VERSION 5.7 ;
BUSBITCHARS "[]" ;
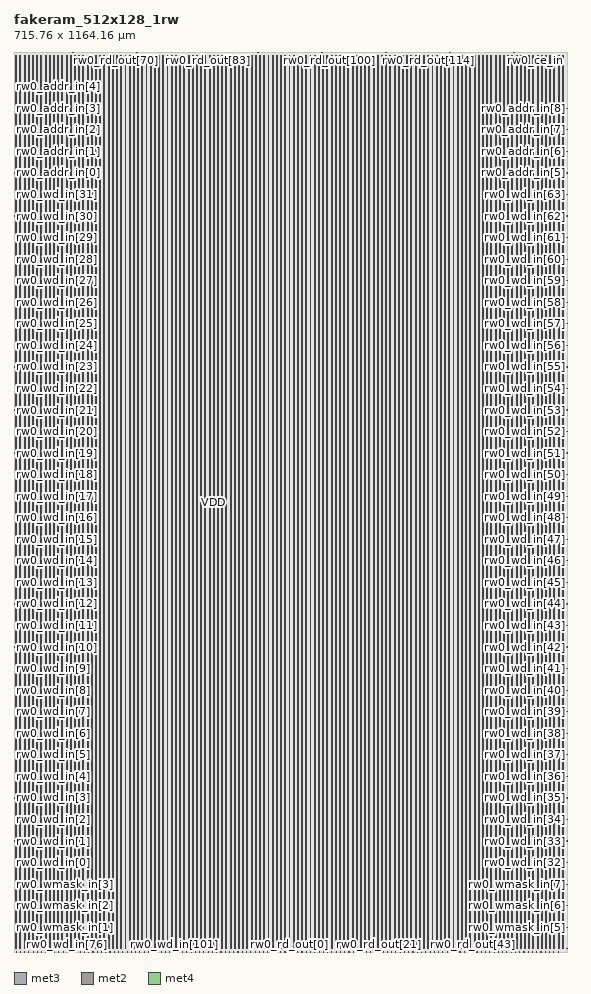
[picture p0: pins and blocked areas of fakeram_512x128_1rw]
MACRO fakeram_512x128_1rw
  FOREIGN fakeram_512x128_1rw 0 0 ;
  SYMMETRY X Y R90 ;
  SIZE 715.760 BY 1164.160 ;
  CLASS BLOCK ;
  PIN rw0_wmask_in[0]
    DIRECTION INPUT ;
    USE SIGNAL ;
    SHAPE ABUTMENT ;
    PORT
      LAYER met3 ;
      RECT 0.000 3.930 0.900 4.230 ;
    END
  END rw0_wmask_in[0]
  PIN rw0_wmask_in[1]
    DIRECTION INPUT ;
    USE SIGNAL ;
    SHAPE ABUTMENT ;
    PORT
      LAYER met3 ;
      RECT 0.000 31.810 0.900 32.110 ;
    END
  END rw0_wmask_in[1]
  PIN rw0_wmask_in[2]
    DIRECTION INPUT ;
    USE SIGNAL ;
    SHAPE ABUTMENT ;
    PORT
      LAYER met3 ;
      RECT 0.000 59.690 0.900 59.990 ;
    END
  END rw0_wmask_in[2]
  PIN rw0_wmask_in[3]
    DIRECTION INPUT ;
    USE SIGNAL ;
    SHAPE ABUTMENT ;
    PORT
      LAYER met3 ;
      RECT 0.000 87.570 0.900 87.870 ;
    END
  END rw0_wmask_in[3]
  PIN rw0_wmask_in[4]
    DIRECTION INPUT ;
    USE SIGNAL ;
    SHAPE ABUTMENT ;
    PORT
      LAYER met3 ;
      RECT 714.860 3.930 715.760 4.230 ;
    END
  END rw0_wmask_in[4]
  PIN rw0_wmask_in[5]
    DIRECTION INPUT ;
    USE SIGNAL ;
    SHAPE ABUTMENT ;
    PORT
      LAYER met3 ;
      RECT 714.860 31.810 715.760 32.110 ;
    END
  END rw0_wmask_in[5]
  PIN rw0_wmask_in[6]
    DIRECTION INPUT ;
    USE SIGNAL ;
    SHAPE ABUTMENT ;
    PORT
      LAYER met3 ;
      RECT 714.860 59.690 715.760 59.990 ;
    END
  END rw0_wmask_in[6]
  PIN rw0_wmask_in[7]
    DIRECTION INPUT ;
    USE SIGNAL ;
    SHAPE ABUTMENT ;
    PORT
      LAYER met3 ;
      RECT 714.860 87.570 715.760 87.870 ;
    END
  END rw0_wmask_in[7]
  PIN rw0_wmask_in[8]
    DIRECTION INPUT ;
    USE SIGNAL ;
    SHAPE ABUTMENT ;
    PORT
      LAYER met2 ;
      RECT 2.690 1163.740 2.830 1164.160 ;
    END
  END rw0_wmask_in[8]
  PIN rw0_wmask_in[9]
    DIRECTION INPUT ;
    USE SIGNAL ;
    SHAPE ABUTMENT ;
    PORT
      LAYER met2 ;
      RECT 11.890 1163.740 12.030 1164.160 ;
    END
  END rw0_wmask_in[9]
  PIN rw0_wmask_in[10]
    DIRECTION INPUT ;
    USE SIGNAL ;
    SHAPE ABUTMENT ;
    PORT
      LAYER met2 ;
      RECT 21.090 1163.740 21.230 1164.160 ;
    END
  END rw0_wmask_in[10]
  PIN rw0_wmask_in[11]
    DIRECTION INPUT ;
    USE SIGNAL ;
    SHAPE ABUTMENT ;
    PORT
      LAYER met2 ;
      RECT 30.290 1163.740 30.430 1164.160 ;
    END
  END rw0_wmask_in[11]
  PIN rw0_wmask_in[12]
    DIRECTION INPUT ;
    USE SIGNAL ;
    SHAPE ABUTMENT ;
    PORT
      LAYER met2 ;
      RECT 39.490 1163.740 39.630 1164.160 ;
    END
  END rw0_wmask_in[12]
  PIN rw0_wmask_in[13]
    DIRECTION INPUT ;
    USE SIGNAL ;
    SHAPE ABUTMENT ;
    PORT
      LAYER met2 ;
      RECT 48.690 1163.740 48.830 1164.160 ;
    END
  END rw0_wmask_in[13]
  PIN rw0_wmask_in[14]
    DIRECTION INPUT ;
    USE SIGNAL ;
    SHAPE ABUTMENT ;
    PORT
      LAYER met2 ;
      RECT 57.890 1163.740 58.030 1164.160 ;
    END
  END rw0_wmask_in[14]
  PIN rw0_wmask_in[15]
    DIRECTION INPUT ;
    USE SIGNAL ;
    SHAPE ABUTMENT ;
    PORT
      LAYER met2 ;
      RECT 67.090 1163.740 67.230 1164.160 ;
    END
  END rw0_wmask_in[15]
  PIN rw0_wd_in[0]
    DIRECTION INPUT ;
    USE SIGNAL ;
    SHAPE ABUTMENT ;
    PORT
      LAYER met3 ;
      RECT 0.000 115.450 0.900 115.750 ;
    END
  END rw0_wd_in[0]
  PIN rw0_wd_in[1]
    DIRECTION INPUT ;
    USE SIGNAL ;
    SHAPE ABUTMENT ;
    PORT
      LAYER met3 ;
      RECT 0.000 143.330 0.900 143.630 ;
    END
  END rw0_wd_in[1]
  PIN rw0_wd_in[2]
    DIRECTION INPUT ;
    USE SIGNAL ;
    SHAPE ABUTMENT ;
    PORT
      LAYER met3 ;
      RECT 0.000 171.210 0.900 171.510 ;
    END
  END rw0_wd_in[2]
  PIN rw0_wd_in[3]
    DIRECTION INPUT ;
    USE SIGNAL ;
    SHAPE ABUTMENT ;
    PORT
      LAYER met3 ;
      RECT 0.000 199.090 0.900 199.390 ;
    END
  END rw0_wd_in[3]
  PIN rw0_wd_in[4]
    DIRECTION INPUT ;
    USE SIGNAL ;
    SHAPE ABUTMENT ;
    PORT
      LAYER met3 ;
      RECT 0.000 226.970 0.900 227.270 ;
    END
  END rw0_wd_in[4]
  PIN rw0_wd_in[5]
    DIRECTION INPUT ;
    USE SIGNAL ;
    SHAPE ABUTMENT ;
    PORT
      LAYER met3 ;
      RECT 0.000 254.850 0.900 255.150 ;
    END
  END rw0_wd_in[5]
  PIN rw0_wd_in[6]
    DIRECTION INPUT ;
    USE SIGNAL ;
    SHAPE ABUTMENT ;
    PORT
      LAYER met3 ;
      RECT 0.000 282.730 0.900 283.030 ;
    END
  END rw0_wd_in[6]
  PIN rw0_wd_in[7]
    DIRECTION INPUT ;
    USE SIGNAL ;
    SHAPE ABUTMENT ;
    PORT
      LAYER met3 ;
      RECT 0.000 310.610 0.900 310.910 ;
    END
  END rw0_wd_in[7]
  PIN rw0_wd_in[8]
    DIRECTION INPUT ;
    USE SIGNAL ;
    SHAPE ABUTMENT ;
    PORT
      LAYER met3 ;
      RECT 0.000 338.490 0.900 338.790 ;
    END
  END rw0_wd_in[8]
  PIN rw0_wd_in[9]
    DIRECTION INPUT ;
    USE SIGNAL ;
    SHAPE ABUTMENT ;
    PORT
      LAYER met3 ;
      RECT 0.000 366.370 0.900 366.670 ;
    END
  END rw0_wd_in[9]
  PIN rw0_wd_in[10]
    DIRECTION INPUT ;
    USE SIGNAL ;
    SHAPE ABUTMENT ;
    PORT
      LAYER met3 ;
      RECT 0.000 394.250 0.900 394.550 ;
    END
  END rw0_wd_in[10]
  PIN rw0_wd_in[11]
    DIRECTION INPUT ;
    USE SIGNAL ;
    SHAPE ABUTMENT ;
    PORT
      LAYER met3 ;
      RECT 0.000 422.130 0.900 422.430 ;
    END
  END rw0_wd_in[11]
  PIN rw0_wd_in[12]
    DIRECTION INPUT ;
    USE SIGNAL ;
    SHAPE ABUTMENT ;
    PORT
      LAYER met3 ;
      RECT 0.000 450.010 0.900 450.310 ;
    END
  END rw0_wd_in[12]
  PIN rw0_wd_in[13]
    DIRECTION INPUT ;
    USE SIGNAL ;
    SHAPE ABUTMENT ;
    PORT
      LAYER met3 ;
      RECT 0.000 477.890 0.900 478.190 ;
    END
  END rw0_wd_in[13]
  PIN rw0_wd_in[14]
    DIRECTION INPUT ;
    USE SIGNAL ;
    SHAPE ABUTMENT ;
    PORT
      LAYER met3 ;
      RECT 0.000 505.770 0.900 506.070 ;
    END
  END rw0_wd_in[14]
  PIN rw0_wd_in[15]
    DIRECTION INPUT ;
    USE SIGNAL ;
    SHAPE ABUTMENT ;
    PORT
      LAYER met3 ;
      RECT 0.000 533.650 0.900 533.950 ;
    END
  END rw0_wd_in[15]
  PIN rw0_wd_in[16]
    DIRECTION INPUT ;
    USE SIGNAL ;
    SHAPE ABUTMENT ;
    PORT
      LAYER met3 ;
      RECT 0.000 561.530 0.900 561.830 ;
    END
  END rw0_wd_in[16]
  PIN rw0_wd_in[17]
    DIRECTION INPUT ;
    USE SIGNAL ;
    SHAPE ABUTMENT ;
    PORT
      LAYER met3 ;
      RECT 0.000 589.410 0.900 589.710 ;
    END
  END rw0_wd_in[17]
  PIN rw0_wd_in[18]
    DIRECTION INPUT ;
    USE SIGNAL ;
    SHAPE ABUTMENT ;
    PORT
      LAYER met3 ;
      RECT 0.000 617.290 0.900 617.590 ;
    END
  END rw0_wd_in[18]
  PIN rw0_wd_in[19]
    DIRECTION INPUT ;
    USE SIGNAL ;
    SHAPE ABUTMENT ;
    PORT
      LAYER met3 ;
      RECT 0.000 645.170 0.900 645.470 ;
    END
  END rw0_wd_in[19]
  PIN rw0_wd_in[20]
    DIRECTION INPUT ;
    USE SIGNAL ;
    SHAPE ABUTMENT ;
    PORT
      LAYER met3 ;
      RECT 0.000 673.050 0.900 673.350 ;
    END
  END rw0_wd_in[20]
  PIN rw0_wd_in[21]
    DIRECTION INPUT ;
    USE SIGNAL ;
    SHAPE ABUTMENT ;
    PORT
      LAYER met3 ;
      RECT 0.000 700.930 0.900 701.230 ;
    END
  END rw0_wd_in[21]
  PIN rw0_wd_in[22]
    DIRECTION INPUT ;
    USE SIGNAL ;
    SHAPE ABUTMENT ;
    PORT
      LAYER met3 ;
      RECT 0.000 728.810 0.900 729.110 ;
    END
  END rw0_wd_in[22]
  PIN rw0_wd_in[23]
    DIRECTION INPUT ;
    USE SIGNAL ;
    SHAPE ABUTMENT ;
    PORT
      LAYER met3 ;
      RECT 0.000 756.690 0.900 756.990 ;
    END
  END rw0_wd_in[23]
  PIN rw0_wd_in[24]
    DIRECTION INPUT ;
    USE SIGNAL ;
    SHAPE ABUTMENT ;
    PORT
      LAYER met3 ;
      RECT 0.000 784.570 0.900 784.870 ;
    END
  END rw0_wd_in[24]
  PIN rw0_wd_in[25]
    DIRECTION INPUT ;
    USE SIGNAL ;
    SHAPE ABUTMENT ;
    PORT
      LAYER met3 ;
      RECT 0.000 812.450 0.900 812.750 ;
    END
  END rw0_wd_in[25]
  PIN rw0_wd_in[26]
    DIRECTION INPUT ;
    USE SIGNAL ;
    SHAPE ABUTMENT ;
    PORT
      LAYER met3 ;
      RECT 0.000 840.330 0.900 840.630 ;
    END
  END rw0_wd_in[26]
  PIN rw0_wd_in[27]
    DIRECTION INPUT ;
    USE SIGNAL ;
    SHAPE ABUTMENT ;
    PORT
      LAYER met3 ;
      RECT 0.000 868.210 0.900 868.510 ;
    END
  END rw0_wd_in[27]
  PIN rw0_wd_in[28]
    DIRECTION INPUT ;
    USE SIGNAL ;
    SHAPE ABUTMENT ;
    PORT
      LAYER met3 ;
      RECT 0.000 896.090 0.900 896.390 ;
    END
  END rw0_wd_in[28]
  PIN rw0_wd_in[29]
    DIRECTION INPUT ;
    USE SIGNAL ;
    SHAPE ABUTMENT ;
    PORT
      LAYER met3 ;
      RECT 0.000 923.970 0.900 924.270 ;
    END
  END rw0_wd_in[29]
  PIN rw0_wd_in[30]
    DIRECTION INPUT ;
    USE SIGNAL ;
    SHAPE ABUTMENT ;
    PORT
      LAYER met3 ;
      RECT 0.000 951.850 0.900 952.150 ;
    END
  END rw0_wd_in[30]
  PIN rw0_wd_in[31]
    DIRECTION INPUT ;
    USE SIGNAL ;
    SHAPE ABUTMENT ;
    PORT
      LAYER met3 ;
      RECT 0.000 979.730 0.900 980.030 ;
    END
  END rw0_wd_in[31]
  PIN rw0_wd_in[32]
    DIRECTION INPUT ;
    USE SIGNAL ;
    SHAPE ABUTMENT ;
    PORT
      LAYER met3 ;
      RECT 714.860 115.450 715.760 115.750 ;
    END
  END rw0_wd_in[32]
  PIN rw0_wd_in[33]
    DIRECTION INPUT ;
    USE SIGNAL ;
    SHAPE ABUTMENT ;
    PORT
      LAYER met3 ;
      RECT 714.860 143.330 715.760 143.630 ;
    END
  END rw0_wd_in[33]
  PIN rw0_wd_in[34]
    DIRECTION INPUT ;
    USE SIGNAL ;
    SHAPE ABUTMENT ;
    PORT
      LAYER met3 ;
      RECT 714.860 171.210 715.760 171.510 ;
    END
  END rw0_wd_in[34]
  PIN rw0_wd_in[35]
    DIRECTION INPUT ;
    USE SIGNAL ;
    SHAPE ABUTMENT ;
    PORT
      LAYER met3 ;
      RECT 714.860 199.090 715.760 199.390 ;
    END
  END rw0_wd_in[35]
  PIN rw0_wd_in[36]
    DIRECTION INPUT ;
    USE SIGNAL ;
    SHAPE ABUTMENT ;
    PORT
      LAYER met3 ;
      RECT 714.860 226.970 715.760 227.270 ;
    END
  END rw0_wd_in[36]
  PIN rw0_wd_in[37]
    DIRECTION INPUT ;
    USE SIGNAL ;
    SHAPE ABUTMENT ;
    PORT
      LAYER met3 ;
      RECT 714.860 254.850 715.760 255.150 ;
    END
  END rw0_wd_in[37]
  PIN rw0_wd_in[38]
    DIRECTION INPUT ;
    USE SIGNAL ;
    SHAPE ABUTMENT ;
    PORT
      LAYER met3 ;
      RECT 714.860 282.730 715.760 283.030 ;
    END
  END rw0_wd_in[38]
  PIN rw0_wd_in[39]
    DIRECTION INPUT ;
    USE SIGNAL ;
    SHAPE ABUTMENT ;
    PORT
      LAYER met3 ;
      RECT 714.860 310.610 715.760 310.910 ;
    END
  END rw0_wd_in[39]
  PIN rw0_wd_in[40]
    DIRECTION INPUT ;
    USE SIGNAL ;
    SHAPE ABUTMENT ;
    PORT
      LAYER met3 ;
      RECT 714.860 338.490 715.760 338.790 ;
    END
  END rw0_wd_in[40]
  PIN rw0_wd_in[41]
    DIRECTION INPUT ;
    USE SIGNAL ;
    SHAPE ABUTMENT ;
    PORT
      LAYER met3 ;
      RECT 714.860 366.370 715.760 366.670 ;
    END
  END rw0_wd_in[41]
  PIN rw0_wd_in[42]
    DIRECTION INPUT ;
    USE SIGNAL ;
    SHAPE ABUTMENT ;
    PORT
      LAYER met3 ;
      RECT 714.860 394.250 715.760 394.550 ;
    END
  END rw0_wd_in[42]
  PIN rw0_wd_in[43]
    DIRECTION INPUT ;
    USE SIGNAL ;
    SHAPE ABUTMENT ;
    PORT
      LAYER met3 ;
      RECT 714.860 422.130 715.760 422.430 ;
    END
  END rw0_wd_in[43]
  PIN rw0_wd_in[44]
    DIRECTION INPUT ;
    USE SIGNAL ;
    SHAPE ABUTMENT ;
    PORT
      LAYER met3 ;
      RECT 714.860 450.010 715.760 450.310 ;
    END
  END rw0_wd_in[44]
  PIN rw0_wd_in[45]
    DIRECTION INPUT ;
    USE SIGNAL ;
    SHAPE ABUTMENT ;
    PORT
      LAYER met3 ;
      RECT 714.860 477.890 715.760 478.190 ;
    END
  END rw0_wd_in[45]
  PIN rw0_wd_in[46]
    DIRECTION INPUT ;
    USE SIGNAL ;
    SHAPE ABUTMENT ;
    PORT
      LAYER met3 ;
      RECT 714.860 505.770 715.760 506.070 ;
    END
  END rw0_wd_in[46]
  PIN rw0_wd_in[47]
    DIRECTION INPUT ;
    USE SIGNAL ;
    SHAPE ABUTMENT ;
    PORT
      LAYER met3 ;
      RECT 714.860 533.650 715.760 533.950 ;
    END
  END rw0_wd_in[47]
  PIN rw0_wd_in[48]
    DIRECTION INPUT ;
    USE SIGNAL ;
    SHAPE ABUTMENT ;
    PORT
      LAYER met3 ;
      RECT 714.860 561.530 715.760 561.830 ;
    END
  END rw0_wd_in[48]
  PIN rw0_wd_in[49]
    DIRECTION INPUT ;
    USE SIGNAL ;
    SHAPE ABUTMENT ;
    PORT
      LAYER met3 ;
      RECT 714.860 589.410 715.760 589.710 ;
    END
  END rw0_wd_in[49]
  PIN rw0_wd_in[50]
    DIRECTION INPUT ;
    USE SIGNAL ;
    SHAPE ABUTMENT ;
    PORT
      LAYER met3 ;
      RECT 714.860 617.290 715.760 617.590 ;
    END
  END rw0_wd_in[50]
  PIN rw0_wd_in[51]
    DIRECTION INPUT ;
    USE SIGNAL ;
    SHAPE ABUTMENT ;
    PORT
      LAYER met3 ;
      RECT 714.860 645.170 715.760 645.470 ;
    END
  END rw0_wd_in[51]
  PIN rw0_wd_in[52]
    DIRECTION INPUT ;
    USE SIGNAL ;
    SHAPE ABUTMENT ;
    PORT
      LAYER met3 ;
      RECT 714.860 673.050 715.760 673.350 ;
    END
  END rw0_wd_in[52]
  PIN rw0_wd_in[53]
    DIRECTION INPUT ;
    USE SIGNAL ;
    SHAPE ABUTMENT ;
    PORT
      LAYER met3 ;
      RECT 714.860 700.930 715.760 701.230 ;
    END
  END rw0_wd_in[53]
  PIN rw0_wd_in[54]
    DIRECTION INPUT ;
    USE SIGNAL ;
    SHAPE ABUTMENT ;
    PORT
      LAYER met3 ;
      RECT 714.860 728.810 715.760 729.110 ;
    END
  END rw0_wd_in[54]
  PIN rw0_wd_in[55]
    DIRECTION INPUT ;
    USE SIGNAL ;
    SHAPE ABUTMENT ;
    PORT
      LAYER met3 ;
      RECT 714.860 756.690 715.760 756.990 ;
    END
  END rw0_wd_in[55]
  PIN rw0_wd_in[56]
    DIRECTION INPUT ;
    USE SIGNAL ;
    SHAPE ABUTMENT ;
    PORT
      LAYER met3 ;
      RECT 714.860 784.570 715.760 784.870 ;
    END
  END rw0_wd_in[56]
  PIN rw0_wd_in[57]
    DIRECTION INPUT ;
    USE SIGNAL ;
    SHAPE ABUTMENT ;
    PORT
      LAYER met3 ;
      RECT 714.860 812.450 715.760 812.750 ;
    END
  END rw0_wd_in[57]
  PIN rw0_wd_in[58]
    DIRECTION INPUT ;
    USE SIGNAL ;
    SHAPE ABUTMENT ;
    PORT
      LAYER met3 ;
      RECT 714.860 840.330 715.760 840.630 ;
    END
  END rw0_wd_in[58]
  PIN rw0_wd_in[59]
    DIRECTION INPUT ;
    USE SIGNAL ;
    SHAPE ABUTMENT ;
    PORT
      LAYER met3 ;
      RECT 714.860 868.210 715.760 868.510 ;
    END
  END rw0_wd_in[59]
  PIN rw0_wd_in[60]
    DIRECTION INPUT ;
    USE SIGNAL ;
    SHAPE ABUTMENT ;
    PORT
      LAYER met3 ;
      RECT 714.860 896.090 715.760 896.390 ;
    END
  END rw0_wd_in[60]
  PIN rw0_wd_in[61]
    DIRECTION INPUT ;
    USE SIGNAL ;
    SHAPE ABUTMENT ;
    PORT
      LAYER met3 ;
      RECT 714.860 923.970 715.760 924.270 ;
    END
  END rw0_wd_in[61]
  PIN rw0_wd_in[62]
    DIRECTION INPUT ;
    USE SIGNAL ;
    SHAPE ABUTMENT ;
    PORT
      LAYER met3 ;
      RECT 714.860 951.850 715.760 952.150 ;
    END
  END rw0_wd_in[62]
  PIN rw0_wd_in[63]
    DIRECTION INPUT ;
    USE SIGNAL ;
    SHAPE ABUTMENT ;
    PORT
      LAYER met3 ;
      RECT 714.860 979.730 715.760 980.030 ;
    END
  END rw0_wd_in[63]
  PIN rw0_wd_in[64]
    DIRECTION INPUT ;
    USE SIGNAL ;
    SHAPE ABUTMENT ;
    PORT
      LAYER met2 ;
      RECT 2.690 0.000 2.830 0.420 ;
    END
  END rw0_wd_in[64]
  PIN rw0_wd_in[65]
    DIRECTION INPUT ;
    USE SIGNAL ;
    SHAPE ABUTMENT ;
    PORT
      LAYER met2 ;
      RECT 8.210 0.000 8.350 0.420 ;
    END
  END rw0_wd_in[65]
  PIN rw0_wd_in[66]
    DIRECTION INPUT ;
    USE SIGNAL ;
    SHAPE ABUTMENT ;
    PORT
      LAYER met2 ;
      RECT 13.730 0.000 13.870 0.420 ;
    END
  END rw0_wd_in[66]
  PIN rw0_wd_in[67]
    DIRECTION INPUT ;
    USE SIGNAL ;
    SHAPE ABUTMENT ;
    PORT
      LAYER met2 ;
      RECT 19.250 0.000 19.390 0.420 ;
    END
  END rw0_wd_in[67]
  PIN rw0_wd_in[68]
    DIRECTION INPUT ;
    USE SIGNAL ;
    SHAPE ABUTMENT ;
    PORT
      LAYER met2 ;
      RECT 24.770 0.000 24.910 0.420 ;
    END
  END rw0_wd_in[68]
  PIN rw0_wd_in[69]
    DIRECTION INPUT ;
    USE SIGNAL ;
    SHAPE ABUTMENT ;
    PORT
      LAYER met2 ;
      RECT 30.290 0.000 30.430 0.420 ;
    END
  END rw0_wd_in[69]
  PIN rw0_wd_in[70]
    DIRECTION INPUT ;
    USE SIGNAL ;
    SHAPE ABUTMENT ;
    PORT
      LAYER met2 ;
      RECT 35.810 0.000 35.950 0.420 ;
    END
  END rw0_wd_in[70]
  PIN rw0_wd_in[71]
    DIRECTION INPUT ;
    USE SIGNAL ;
    SHAPE ABUTMENT ;
    PORT
      LAYER met2 ;
      RECT 41.330 0.000 41.470 0.420 ;
    END
  END rw0_wd_in[71]
  PIN rw0_wd_in[72]
    DIRECTION INPUT ;
    USE SIGNAL ;
    SHAPE ABUTMENT ;
    PORT
      LAYER met2 ;
      RECT 46.850 0.000 46.990 0.420 ;
    END
  END rw0_wd_in[72]
  PIN rw0_wd_in[73]
    DIRECTION INPUT ;
    USE SIGNAL ;
    SHAPE ABUTMENT ;
    PORT
      LAYER met2 ;
      RECT 52.370 0.000 52.510 0.420 ;
    END
  END rw0_wd_in[73]
  PIN rw0_wd_in[74]
    DIRECTION INPUT ;
    USE SIGNAL ;
    SHAPE ABUTMENT ;
    PORT
      LAYER met2 ;
      RECT 57.890 0.000 58.030 0.420 ;
    END
  END rw0_wd_in[74]
  PIN rw0_wd_in[75]
    DIRECTION INPUT ;
    USE SIGNAL ;
    SHAPE ABUTMENT ;
    PORT
      LAYER met2 ;
      RECT 63.410 0.000 63.550 0.420 ;
    END
  END rw0_wd_in[75]
  PIN rw0_wd_in[76]
    DIRECTION INPUT ;
    USE SIGNAL ;
    SHAPE ABUTMENT ;
    PORT
      LAYER met2 ;
      RECT 68.930 0.000 69.070 0.420 ;
    END
  END rw0_wd_in[76]
  PIN rw0_wd_in[77]
    DIRECTION INPUT ;
    USE SIGNAL ;
    SHAPE ABUTMENT ;
    PORT
      LAYER met2 ;
      RECT 74.450 0.000 74.590 0.420 ;
    END
  END rw0_wd_in[77]
  PIN rw0_wd_in[78]
    DIRECTION INPUT ;
    USE SIGNAL ;
    SHAPE ABUTMENT ;
    PORT
      LAYER met2 ;
      RECT 79.970 0.000 80.110 0.420 ;
    END
  END rw0_wd_in[78]
  PIN rw0_wd_in[79]
    DIRECTION INPUT ;
    USE SIGNAL ;
    SHAPE ABUTMENT ;
    PORT
      LAYER met2 ;
      RECT 85.490 0.000 85.630 0.420 ;
    END
  END rw0_wd_in[79]
  PIN rw0_wd_in[80]
    DIRECTION INPUT ;
    USE SIGNAL ;
    SHAPE ABUTMENT ;
    PORT
      LAYER met2 ;
      RECT 91.010 0.000 91.150 0.420 ;
    END
  END rw0_wd_in[80]
  PIN rw0_wd_in[81]
    DIRECTION INPUT ;
    USE SIGNAL ;
    SHAPE ABUTMENT ;
    PORT
      LAYER met2 ;
      RECT 96.530 0.000 96.670 0.420 ;
    END
  END rw0_wd_in[81]
  PIN rw0_wd_in[82]
    DIRECTION INPUT ;
    USE SIGNAL ;
    SHAPE ABUTMENT ;
    PORT
      LAYER met2 ;
      RECT 102.050 0.000 102.190 0.420 ;
    END
  END rw0_wd_in[82]
  PIN rw0_wd_in[83]
    DIRECTION INPUT ;
    USE SIGNAL ;
    SHAPE ABUTMENT ;
    PORT
      LAYER met2 ;
      RECT 107.570 0.000 107.710 0.420 ;
    END
  END rw0_wd_in[83]
  PIN rw0_wd_in[84]
    DIRECTION INPUT ;
    USE SIGNAL ;
    SHAPE ABUTMENT ;
    PORT
      LAYER met2 ;
      RECT 113.090 0.000 113.230 0.420 ;
    END
  END rw0_wd_in[84]
  PIN rw0_wd_in[85]
    DIRECTION INPUT ;
    USE SIGNAL ;
    SHAPE ABUTMENT ;
    PORT
      LAYER met2 ;
      RECT 118.610 0.000 118.750 0.420 ;
    END
  END rw0_wd_in[85]
  PIN rw0_wd_in[86]
    DIRECTION INPUT ;
    USE SIGNAL ;
    SHAPE ABUTMENT ;
    PORT
      LAYER met2 ;
      RECT 124.130 0.000 124.270 0.420 ;
    END
  END rw0_wd_in[86]
  PIN rw0_wd_in[87]
    DIRECTION INPUT ;
    USE SIGNAL ;
    SHAPE ABUTMENT ;
    PORT
      LAYER met2 ;
      RECT 129.650 0.000 129.790 0.420 ;
    END
  END rw0_wd_in[87]
  PIN rw0_wd_in[88]
    DIRECTION INPUT ;
    USE SIGNAL ;
    SHAPE ABUTMENT ;
    PORT
      LAYER met2 ;
      RECT 135.170 0.000 135.310 0.420 ;
    END
  END rw0_wd_in[88]
  PIN rw0_wd_in[89]
    DIRECTION INPUT ;
    USE SIGNAL ;
    SHAPE ABUTMENT ;
    PORT
      LAYER met2 ;
      RECT 140.690 0.000 140.830 0.420 ;
    END
  END rw0_wd_in[89]
  PIN rw0_wd_in[90]
    DIRECTION INPUT ;
    USE SIGNAL ;
    SHAPE ABUTMENT ;
    PORT
      LAYER met2 ;
      RECT 146.210 0.000 146.350 0.420 ;
    END
  END rw0_wd_in[90]
  PIN rw0_wd_in[91]
    DIRECTION INPUT ;
    USE SIGNAL ;
    SHAPE ABUTMENT ;
    PORT
      LAYER met2 ;
      RECT 151.730 0.000 151.870 0.420 ;
    END
  END rw0_wd_in[91]
  PIN rw0_wd_in[92]
    DIRECTION INPUT ;
    USE SIGNAL ;
    SHAPE ABUTMENT ;
    PORT
      LAYER met2 ;
      RECT 157.250 0.000 157.390 0.420 ;
    END
  END rw0_wd_in[92]
  PIN rw0_wd_in[93]
    DIRECTION INPUT ;
    USE SIGNAL ;
    SHAPE ABUTMENT ;
    PORT
      LAYER met2 ;
      RECT 162.770 0.000 162.910 0.420 ;
    END
  END rw0_wd_in[93]
  PIN rw0_wd_in[94]
    DIRECTION INPUT ;
    USE SIGNAL ;
    SHAPE ABUTMENT ;
    PORT
      LAYER met2 ;
      RECT 168.290 0.000 168.430 0.420 ;
    END
  END rw0_wd_in[94]
  PIN rw0_wd_in[95]
    DIRECTION INPUT ;
    USE SIGNAL ;
    SHAPE ABUTMENT ;
    PORT
      LAYER met2 ;
      RECT 173.810 0.000 173.950 0.420 ;
    END
  END rw0_wd_in[95]
  PIN rw0_wd_in[96]
    DIRECTION INPUT ;
    USE SIGNAL ;
    SHAPE ABUTMENT ;
    PORT
      LAYER met2 ;
      RECT 179.330 0.000 179.470 0.420 ;
    END
  END rw0_wd_in[96]
  PIN rw0_wd_in[97]
    DIRECTION INPUT ;
    USE SIGNAL ;
    SHAPE ABUTMENT ;
    PORT
      LAYER met2 ;
      RECT 184.850 0.000 184.990 0.420 ;
    END
  END rw0_wd_in[97]
  PIN rw0_wd_in[98]
    DIRECTION INPUT ;
    USE SIGNAL ;
    SHAPE ABUTMENT ;
    PORT
      LAYER met2 ;
      RECT 190.370 0.000 190.510 0.420 ;
    END
  END rw0_wd_in[98]
  PIN rw0_wd_in[99]
    DIRECTION INPUT ;
    USE SIGNAL ;
    SHAPE ABUTMENT ;
    PORT
      LAYER met2 ;
      RECT 195.890 0.000 196.030 0.420 ;
    END
  END rw0_wd_in[99]
  PIN rw0_wd_in[100]
    DIRECTION INPUT ;
    USE SIGNAL ;
    SHAPE ABUTMENT ;
    PORT
      LAYER met2 ;
      RECT 201.410 0.000 201.550 0.420 ;
    END
  END rw0_wd_in[100]
  PIN rw0_wd_in[101]
    DIRECTION INPUT ;
    USE SIGNAL ;
    SHAPE ABUTMENT ;
    PORT
      LAYER met2 ;
      RECT 206.930 0.000 207.070 0.420 ;
    END
  END rw0_wd_in[101]
  PIN rw0_wd_in[102]
    DIRECTION INPUT ;
    USE SIGNAL ;
    SHAPE ABUTMENT ;
    PORT
      LAYER met2 ;
      RECT 212.450 0.000 212.590 0.420 ;
    END
  END rw0_wd_in[102]
  PIN rw0_wd_in[103]
    DIRECTION INPUT ;
    USE SIGNAL ;
    SHAPE ABUTMENT ;
    PORT
      LAYER met2 ;
      RECT 217.970 0.000 218.110 0.420 ;
    END
  END rw0_wd_in[103]
  PIN rw0_wd_in[104]
    DIRECTION INPUT ;
    USE SIGNAL ;
    SHAPE ABUTMENT ;
    PORT
      LAYER met2 ;
      RECT 223.490 0.000 223.630 0.420 ;
    END
  END rw0_wd_in[104]
  PIN rw0_wd_in[105]
    DIRECTION INPUT ;
    USE SIGNAL ;
    SHAPE ABUTMENT ;
    PORT
      LAYER met2 ;
      RECT 229.010 0.000 229.150 0.420 ;
    END
  END rw0_wd_in[105]
  PIN rw0_wd_in[106]
    DIRECTION INPUT ;
    USE SIGNAL ;
    SHAPE ABUTMENT ;
    PORT
      LAYER met2 ;
      RECT 234.530 0.000 234.670 0.420 ;
    END
  END rw0_wd_in[106]
  PIN rw0_wd_in[107]
    DIRECTION INPUT ;
    USE SIGNAL ;
    SHAPE ABUTMENT ;
    PORT
      LAYER met2 ;
      RECT 240.050 0.000 240.190 0.420 ;
    END
  END rw0_wd_in[107]
  PIN rw0_wd_in[108]
    DIRECTION INPUT ;
    USE SIGNAL ;
    SHAPE ABUTMENT ;
    PORT
      LAYER met2 ;
      RECT 245.570 0.000 245.710 0.420 ;
    END
  END rw0_wd_in[108]
  PIN rw0_wd_in[109]
    DIRECTION INPUT ;
    USE SIGNAL ;
    SHAPE ABUTMENT ;
    PORT
      LAYER met2 ;
      RECT 251.090 0.000 251.230 0.420 ;
    END
  END rw0_wd_in[109]
  PIN rw0_wd_in[110]
    DIRECTION INPUT ;
    USE SIGNAL ;
    SHAPE ABUTMENT ;
    PORT
      LAYER met2 ;
      RECT 256.610 0.000 256.750 0.420 ;
    END
  END rw0_wd_in[110]
  PIN rw0_wd_in[111]
    DIRECTION INPUT ;
    USE SIGNAL ;
    SHAPE ABUTMENT ;
    PORT
      LAYER met2 ;
      RECT 262.130 0.000 262.270 0.420 ;
    END
  END rw0_wd_in[111]
  PIN rw0_wd_in[112]
    DIRECTION INPUT ;
    USE SIGNAL ;
    SHAPE ABUTMENT ;
    PORT
      LAYER met2 ;
      RECT 267.650 0.000 267.790 0.420 ;
    END
  END rw0_wd_in[112]
  PIN rw0_wd_in[113]
    DIRECTION INPUT ;
    USE SIGNAL ;
    SHAPE ABUTMENT ;
    PORT
      LAYER met2 ;
      RECT 273.170 0.000 273.310 0.420 ;
    END
  END rw0_wd_in[113]
  PIN rw0_wd_in[114]
    DIRECTION INPUT ;
    USE SIGNAL ;
    SHAPE ABUTMENT ;
    PORT
      LAYER met2 ;
      RECT 278.690 0.000 278.830 0.420 ;
    END
  END rw0_wd_in[114]
  PIN rw0_wd_in[115]
    DIRECTION INPUT ;
    USE SIGNAL ;
    SHAPE ABUTMENT ;
    PORT
      LAYER met2 ;
      RECT 284.210 0.000 284.350 0.420 ;
    END
  END rw0_wd_in[115]
  PIN rw0_wd_in[116]
    DIRECTION INPUT ;
    USE SIGNAL ;
    SHAPE ABUTMENT ;
    PORT
      LAYER met2 ;
      RECT 289.730 0.000 289.870 0.420 ;
    END
  END rw0_wd_in[116]
  PIN rw0_wd_in[117]
    DIRECTION INPUT ;
    USE SIGNAL ;
    SHAPE ABUTMENT ;
    PORT
      LAYER met2 ;
      RECT 295.250 0.000 295.390 0.420 ;
    END
  END rw0_wd_in[117]
  PIN rw0_wd_in[118]
    DIRECTION INPUT ;
    USE SIGNAL ;
    SHAPE ABUTMENT ;
    PORT
      LAYER met2 ;
      RECT 300.770 0.000 300.910 0.420 ;
    END
  END rw0_wd_in[118]
  PIN rw0_wd_in[119]
    DIRECTION INPUT ;
    USE SIGNAL ;
    SHAPE ABUTMENT ;
    PORT
      LAYER met2 ;
      RECT 306.290 0.000 306.430 0.420 ;
    END
  END rw0_wd_in[119]
  PIN rw0_wd_in[120]
    DIRECTION INPUT ;
    USE SIGNAL ;
    SHAPE ABUTMENT ;
    PORT
      LAYER met2 ;
      RECT 311.810 0.000 311.950 0.420 ;
    END
  END rw0_wd_in[120]
  PIN rw0_wd_in[121]
    DIRECTION INPUT ;
    USE SIGNAL ;
    SHAPE ABUTMENT ;
    PORT
      LAYER met2 ;
      RECT 317.330 0.000 317.470 0.420 ;
    END
  END rw0_wd_in[121]
  PIN rw0_wd_in[122]
    DIRECTION INPUT ;
    USE SIGNAL ;
    SHAPE ABUTMENT ;
    PORT
      LAYER met2 ;
      RECT 322.850 0.000 322.990 0.420 ;
    END
  END rw0_wd_in[122]
  PIN rw0_wd_in[123]
    DIRECTION INPUT ;
    USE SIGNAL ;
    SHAPE ABUTMENT ;
    PORT
      LAYER met2 ;
      RECT 328.370 0.000 328.510 0.420 ;
    END
  END rw0_wd_in[123]
  PIN rw0_wd_in[124]
    DIRECTION INPUT ;
    USE SIGNAL ;
    SHAPE ABUTMENT ;
    PORT
      LAYER met2 ;
      RECT 333.890 0.000 334.030 0.420 ;
    END
  END rw0_wd_in[124]
  PIN rw0_wd_in[125]
    DIRECTION INPUT ;
    USE SIGNAL ;
    SHAPE ABUTMENT ;
    PORT
      LAYER met2 ;
      RECT 339.410 0.000 339.550 0.420 ;
    END
  END rw0_wd_in[125]
  PIN rw0_wd_in[126]
    DIRECTION INPUT ;
    USE SIGNAL ;
    SHAPE ABUTMENT ;
    PORT
      LAYER met2 ;
      RECT 344.930 0.000 345.070 0.420 ;
    END
  END rw0_wd_in[126]
  PIN rw0_wd_in[127]
    DIRECTION INPUT ;
    USE SIGNAL ;
    SHAPE ABUTMENT ;
    PORT
      LAYER met2 ;
      RECT 350.450 0.000 350.590 0.420 ;
    END
  END rw0_wd_in[127]
  PIN rw0_rd_out[0]
    DIRECTION OUTPUT ;
    USE SIGNAL ;
    SHAPE ABUTMENT ;
    PORT
      LAYER met2 ;
      RECT 355.970 0.000 356.110 0.420 ;
    END
  END rw0_rd_out[0]
  PIN rw0_rd_out[1]
    DIRECTION OUTPUT ;
    USE SIGNAL ;
    SHAPE ABUTMENT ;
    PORT
      LAYER met2 ;
      RECT 361.490 0.000 361.630 0.420 ;
    END
  END rw0_rd_out[1]
  PIN rw0_rd_out[2]
    DIRECTION OUTPUT ;
    USE SIGNAL ;
    SHAPE ABUTMENT ;
    PORT
      LAYER met2 ;
      RECT 367.010 0.000 367.150 0.420 ;
    END
  END rw0_rd_out[2]
  PIN rw0_rd_out[3]
    DIRECTION OUTPUT ;
    USE SIGNAL ;
    SHAPE ABUTMENT ;
    PORT
      LAYER met2 ;
      RECT 372.530 0.000 372.670 0.420 ;
    END
  END rw0_rd_out[3]
  PIN rw0_rd_out[4]
    DIRECTION OUTPUT ;
    USE SIGNAL ;
    SHAPE ABUTMENT ;
    PORT
      LAYER met2 ;
      RECT 378.050 0.000 378.190 0.420 ;
    END
  END rw0_rd_out[4]
  PIN rw0_rd_out[5]
    DIRECTION OUTPUT ;
    USE SIGNAL ;
    SHAPE ABUTMENT ;
    PORT
      LAYER met2 ;
      RECT 383.570 0.000 383.710 0.420 ;
    END
  END rw0_rd_out[5]
  PIN rw0_rd_out[6]
    DIRECTION OUTPUT ;
    USE SIGNAL ;
    SHAPE ABUTMENT ;
    PORT
      LAYER met2 ;
      RECT 389.090 0.000 389.230 0.420 ;
    END
  END rw0_rd_out[6]
  PIN rw0_rd_out[7]
    DIRECTION OUTPUT ;
    USE SIGNAL ;
    SHAPE ABUTMENT ;
    PORT
      LAYER met2 ;
      RECT 394.610 0.000 394.750 0.420 ;
    END
  END rw0_rd_out[7]
  PIN rw0_rd_out[8]
    DIRECTION OUTPUT ;
    USE SIGNAL ;
    SHAPE ABUTMENT ;
    PORT
      LAYER met2 ;
      RECT 400.130 0.000 400.270 0.420 ;
    END
  END rw0_rd_out[8]
  PIN rw0_rd_out[9]
    DIRECTION OUTPUT ;
    USE SIGNAL ;
    SHAPE ABUTMENT ;
    PORT
      LAYER met2 ;
      RECT 405.650 0.000 405.790 0.420 ;
    END
  END rw0_rd_out[9]
  PIN rw0_rd_out[10]
    DIRECTION OUTPUT ;
    USE SIGNAL ;
    SHAPE ABUTMENT ;
    PORT
      LAYER met2 ;
      RECT 411.170 0.000 411.310 0.420 ;
    END
  END rw0_rd_out[10]
  PIN rw0_rd_out[11]
    DIRECTION OUTPUT ;
    USE SIGNAL ;
    SHAPE ABUTMENT ;
    PORT
      LAYER met2 ;
      RECT 416.690 0.000 416.830 0.420 ;
    END
  END rw0_rd_out[11]
  PIN rw0_rd_out[12]
    DIRECTION OUTPUT ;
    USE SIGNAL ;
    SHAPE ABUTMENT ;
    PORT
      LAYER met2 ;
      RECT 422.210 0.000 422.350 0.420 ;
    END
  END rw0_rd_out[12]
  PIN rw0_rd_out[13]
    DIRECTION OUTPUT ;
    USE SIGNAL ;
    SHAPE ABUTMENT ;
    PORT
      LAYER met2 ;
      RECT 427.730 0.000 427.870 0.420 ;
    END
  END rw0_rd_out[13]
  PIN rw0_rd_out[14]
    DIRECTION OUTPUT ;
    USE SIGNAL ;
    SHAPE ABUTMENT ;
    PORT
      LAYER met2 ;
      RECT 433.250 0.000 433.390 0.420 ;
    END
  END rw0_rd_out[14]
  PIN rw0_rd_out[15]
    DIRECTION OUTPUT ;
    USE SIGNAL ;
    SHAPE ABUTMENT ;
    PORT
      LAYER met2 ;
      RECT 438.770 0.000 438.910 0.420 ;
    END
  END rw0_rd_out[15]
  PIN rw0_rd_out[16]
    DIRECTION OUTPUT ;
    USE SIGNAL ;
    SHAPE ABUTMENT ;
    PORT
      LAYER met2 ;
      RECT 444.290 0.000 444.430 0.420 ;
    END
  END rw0_rd_out[16]
  PIN rw0_rd_out[17]
    DIRECTION OUTPUT ;
    USE SIGNAL ;
    SHAPE ABUTMENT ;
    PORT
      LAYER met2 ;
      RECT 449.810 0.000 449.950 0.420 ;
    END
  END rw0_rd_out[17]
  PIN rw0_rd_out[18]
    DIRECTION OUTPUT ;
    USE SIGNAL ;
    SHAPE ABUTMENT ;
    PORT
      LAYER met2 ;
      RECT 455.330 0.000 455.470 0.420 ;
    END
  END rw0_rd_out[18]
  PIN rw0_rd_out[19]
    DIRECTION OUTPUT ;
    USE SIGNAL ;
    SHAPE ABUTMENT ;
    PORT
      LAYER met2 ;
      RECT 460.850 0.000 460.990 0.420 ;
    END
  END rw0_rd_out[19]
  PIN rw0_rd_out[20]
    DIRECTION OUTPUT ;
    USE SIGNAL ;
    SHAPE ABUTMENT ;
    PORT
      LAYER met2 ;
      RECT 466.370 0.000 466.510 0.420 ;
    END
  END rw0_rd_out[20]
  PIN rw0_rd_out[21]
    DIRECTION OUTPUT ;
    USE SIGNAL ;
    SHAPE ABUTMENT ;
    PORT
      LAYER met2 ;
      RECT 471.890 0.000 472.030 0.420 ;
    END
  END rw0_rd_out[21]
  PIN rw0_rd_out[22]
    DIRECTION OUTPUT ;
    USE SIGNAL ;
    SHAPE ABUTMENT ;
    PORT
      LAYER met2 ;
      RECT 477.410 0.000 477.550 0.420 ;
    END
  END rw0_rd_out[22]
  PIN rw0_rd_out[23]
    DIRECTION OUTPUT ;
    USE SIGNAL ;
    SHAPE ABUTMENT ;
    PORT
      LAYER met2 ;
      RECT 482.930 0.000 483.070 0.420 ;
    END
  END rw0_rd_out[23]
  PIN rw0_rd_out[24]
    DIRECTION OUTPUT ;
    USE SIGNAL ;
    SHAPE ABUTMENT ;
    PORT
      LAYER met2 ;
      RECT 488.450 0.000 488.590 0.420 ;
    END
  END rw0_rd_out[24]
  PIN rw0_rd_out[25]
    DIRECTION OUTPUT ;
    USE SIGNAL ;
    SHAPE ABUTMENT ;
    PORT
      LAYER met2 ;
      RECT 493.970 0.000 494.110 0.420 ;
    END
  END rw0_rd_out[25]
  PIN rw0_rd_out[26]
    DIRECTION OUTPUT ;
    USE SIGNAL ;
    SHAPE ABUTMENT ;
    PORT
      LAYER met2 ;
      RECT 499.490 0.000 499.630 0.420 ;
    END
  END rw0_rd_out[26]
  PIN rw0_rd_out[27]
    DIRECTION OUTPUT ;
    USE SIGNAL ;
    SHAPE ABUTMENT ;
    PORT
      LAYER met2 ;
      RECT 505.010 0.000 505.150 0.420 ;
    END
  END rw0_rd_out[27]
  PIN rw0_rd_out[28]
    DIRECTION OUTPUT ;
    USE SIGNAL ;
    SHAPE ABUTMENT ;
    PORT
      LAYER met2 ;
      RECT 510.530 0.000 510.670 0.420 ;
    END
  END rw0_rd_out[28]
  PIN rw0_rd_out[29]
    DIRECTION OUTPUT ;
    USE SIGNAL ;
    SHAPE ABUTMENT ;
    PORT
      LAYER met2 ;
      RECT 516.050 0.000 516.190 0.420 ;
    END
  END rw0_rd_out[29]
  PIN rw0_rd_out[30]
    DIRECTION OUTPUT ;
    USE SIGNAL ;
    SHAPE ABUTMENT ;
    PORT
      LAYER met2 ;
      RECT 521.570 0.000 521.710 0.420 ;
    END
  END rw0_rd_out[30]
  PIN rw0_rd_out[31]
    DIRECTION OUTPUT ;
    USE SIGNAL ;
    SHAPE ABUTMENT ;
    PORT
      LAYER met2 ;
      RECT 527.090 0.000 527.230 0.420 ;
    END
  END rw0_rd_out[31]
  PIN rw0_rd_out[32]
    DIRECTION OUTPUT ;
    USE SIGNAL ;
    SHAPE ABUTMENT ;
    PORT
      LAYER met2 ;
      RECT 532.610 0.000 532.750 0.420 ;
    END
  END rw0_rd_out[32]
  PIN rw0_rd_out[33]
    DIRECTION OUTPUT ;
    USE SIGNAL ;
    SHAPE ABUTMENT ;
    PORT
      LAYER met2 ;
      RECT 538.130 0.000 538.270 0.420 ;
    END
  END rw0_rd_out[33]
  PIN rw0_rd_out[34]
    DIRECTION OUTPUT ;
    USE SIGNAL ;
    SHAPE ABUTMENT ;
    PORT
      LAYER met2 ;
      RECT 543.650 0.000 543.790 0.420 ;
    END
  END rw0_rd_out[34]
  PIN rw0_rd_out[35]
    DIRECTION OUTPUT ;
    USE SIGNAL ;
    SHAPE ABUTMENT ;
    PORT
      LAYER met2 ;
      RECT 549.170 0.000 549.310 0.420 ;
    END
  END rw0_rd_out[35]
  PIN rw0_rd_out[36]
    DIRECTION OUTPUT ;
    USE SIGNAL ;
    SHAPE ABUTMENT ;
    PORT
      LAYER met2 ;
      RECT 554.690 0.000 554.830 0.420 ;
    END
  END rw0_rd_out[36]
  PIN rw0_rd_out[37]
    DIRECTION OUTPUT ;
    USE SIGNAL ;
    SHAPE ABUTMENT ;
    PORT
      LAYER met2 ;
      RECT 560.210 0.000 560.350 0.420 ;
    END
  END rw0_rd_out[37]
  PIN rw0_rd_out[38]
    DIRECTION OUTPUT ;
    USE SIGNAL ;
    SHAPE ABUTMENT ;
    PORT
      LAYER met2 ;
      RECT 565.730 0.000 565.870 0.420 ;
    END
  END rw0_rd_out[38]
  PIN rw0_rd_out[39]
    DIRECTION OUTPUT ;
    USE SIGNAL ;
    SHAPE ABUTMENT ;
    PORT
      LAYER met2 ;
      RECT 571.250 0.000 571.390 0.420 ;
    END
  END rw0_rd_out[39]
  PIN rw0_rd_out[40]
    DIRECTION OUTPUT ;
    USE SIGNAL ;
    SHAPE ABUTMENT ;
    PORT
      LAYER met2 ;
      RECT 576.770 0.000 576.910 0.420 ;
    END
  END rw0_rd_out[40]
  PIN rw0_rd_out[41]
    DIRECTION OUTPUT ;
    USE SIGNAL ;
    SHAPE ABUTMENT ;
    PORT
      LAYER met2 ;
      RECT 582.290 0.000 582.430 0.420 ;
    END
  END rw0_rd_out[41]
  PIN rw0_rd_out[42]
    DIRECTION OUTPUT ;
    USE SIGNAL ;
    SHAPE ABUTMENT ;
    PORT
      LAYER met2 ;
      RECT 587.810 0.000 587.950 0.420 ;
    END
  END rw0_rd_out[42]
  PIN rw0_rd_out[43]
    DIRECTION OUTPUT ;
    USE SIGNAL ;
    SHAPE ABUTMENT ;
    PORT
      LAYER met2 ;
      RECT 593.330 0.000 593.470 0.420 ;
    END
  END rw0_rd_out[43]
  PIN rw0_rd_out[44]
    DIRECTION OUTPUT ;
    USE SIGNAL ;
    SHAPE ABUTMENT ;
    PORT
      LAYER met2 ;
      RECT 598.850 0.000 598.990 0.420 ;
    END
  END rw0_rd_out[44]
  PIN rw0_rd_out[45]
    DIRECTION OUTPUT ;
    USE SIGNAL ;
    SHAPE ABUTMENT ;
    PORT
      LAYER met2 ;
      RECT 604.370 0.000 604.510 0.420 ;
    END
  END rw0_rd_out[45]
  PIN rw0_rd_out[46]
    DIRECTION OUTPUT ;
    USE SIGNAL ;
    SHAPE ABUTMENT ;
    PORT
      LAYER met2 ;
      RECT 609.890 0.000 610.030 0.420 ;
    END
  END rw0_rd_out[46]
  PIN rw0_rd_out[47]
    DIRECTION OUTPUT ;
    USE SIGNAL ;
    SHAPE ABUTMENT ;
    PORT
      LAYER met2 ;
      RECT 615.410 0.000 615.550 0.420 ;
    END
  END rw0_rd_out[47]
  PIN rw0_rd_out[48]
    DIRECTION OUTPUT ;
    USE SIGNAL ;
    SHAPE ABUTMENT ;
    PORT
      LAYER met2 ;
      RECT 620.930 0.000 621.070 0.420 ;
    END
  END rw0_rd_out[48]
  PIN rw0_rd_out[49]
    DIRECTION OUTPUT ;
    USE SIGNAL ;
    SHAPE ABUTMENT ;
    PORT
      LAYER met2 ;
      RECT 626.450 0.000 626.590 0.420 ;
    END
  END rw0_rd_out[49]
  PIN rw0_rd_out[50]
    DIRECTION OUTPUT ;
    USE SIGNAL ;
    SHAPE ABUTMENT ;
    PORT
      LAYER met2 ;
      RECT 631.970 0.000 632.110 0.420 ;
    END
  END rw0_rd_out[50]
  PIN rw0_rd_out[51]
    DIRECTION OUTPUT ;
    USE SIGNAL ;
    SHAPE ABUTMENT ;
    PORT
      LAYER met2 ;
      RECT 637.490 0.000 637.630 0.420 ;
    END
  END rw0_rd_out[51]
  PIN rw0_rd_out[52]
    DIRECTION OUTPUT ;
    USE SIGNAL ;
    SHAPE ABUTMENT ;
    PORT
      LAYER met2 ;
      RECT 643.010 0.000 643.150 0.420 ;
    END
  END rw0_rd_out[52]
  PIN rw0_rd_out[53]
    DIRECTION OUTPUT ;
    USE SIGNAL ;
    SHAPE ABUTMENT ;
    PORT
      LAYER met2 ;
      RECT 648.530 0.000 648.670 0.420 ;
    END
  END rw0_rd_out[53]
  PIN rw0_rd_out[54]
    DIRECTION OUTPUT ;
    USE SIGNAL ;
    SHAPE ABUTMENT ;
    PORT
      LAYER met2 ;
      RECT 654.050 0.000 654.190 0.420 ;
    END
  END rw0_rd_out[54]
  PIN rw0_rd_out[55]
    DIRECTION OUTPUT ;
    USE SIGNAL ;
    SHAPE ABUTMENT ;
    PORT
      LAYER met2 ;
      RECT 659.570 0.000 659.710 0.420 ;
    END
  END rw0_rd_out[55]
  PIN rw0_rd_out[56]
    DIRECTION OUTPUT ;
    USE SIGNAL ;
    SHAPE ABUTMENT ;
    PORT
      LAYER met2 ;
      RECT 665.090 0.000 665.230 0.420 ;
    END
  END rw0_rd_out[56]
  PIN rw0_rd_out[57]
    DIRECTION OUTPUT ;
    USE SIGNAL ;
    SHAPE ABUTMENT ;
    PORT
      LAYER met2 ;
      RECT 670.610 0.000 670.750 0.420 ;
    END
  END rw0_rd_out[57]
  PIN rw0_rd_out[58]
    DIRECTION OUTPUT ;
    USE SIGNAL ;
    SHAPE ABUTMENT ;
    PORT
      LAYER met2 ;
      RECT 676.130 0.000 676.270 0.420 ;
    END
  END rw0_rd_out[58]
  PIN rw0_rd_out[59]
    DIRECTION OUTPUT ;
    USE SIGNAL ;
    SHAPE ABUTMENT ;
    PORT
      LAYER met2 ;
      RECT 681.650 0.000 681.790 0.420 ;
    END
  END rw0_rd_out[59]
  PIN rw0_rd_out[60]
    DIRECTION OUTPUT ;
    USE SIGNAL ;
    SHAPE ABUTMENT ;
    PORT
      LAYER met2 ;
      RECT 687.170 0.000 687.310 0.420 ;
    END
  END rw0_rd_out[60]
  PIN rw0_rd_out[61]
    DIRECTION OUTPUT ;
    USE SIGNAL ;
    SHAPE ABUTMENT ;
    PORT
      LAYER met2 ;
      RECT 692.690 0.000 692.830 0.420 ;
    END
  END rw0_rd_out[61]
  PIN rw0_rd_out[62]
    DIRECTION OUTPUT ;
    USE SIGNAL ;
    SHAPE ABUTMENT ;
    PORT
      LAYER met2 ;
      RECT 698.210 0.000 698.350 0.420 ;
    END
  END rw0_rd_out[62]
  PIN rw0_rd_out[63]
    DIRECTION OUTPUT ;
    USE SIGNAL ;
    SHAPE ABUTMENT ;
    PORT
      LAYER met2 ;
      RECT 703.730 0.000 703.870 0.420 ;
    END
  END rw0_rd_out[63]
  PIN rw0_rd_out[64]
    DIRECTION OUTPUT ;
    USE SIGNAL ;
    SHAPE ABUTMENT ;
    PORT
      LAYER met2 ;
      RECT 76.290 1163.740 76.430 1164.160 ;
    END
  END rw0_rd_out[64]
  PIN rw0_rd_out[65]
    DIRECTION OUTPUT ;
    USE SIGNAL ;
    SHAPE ABUTMENT ;
    PORT
      LAYER met2 ;
      RECT 85.490 1163.740 85.630 1164.160 ;
    END
  END rw0_rd_out[65]
  PIN rw0_rd_out[66]
    DIRECTION OUTPUT ;
    USE SIGNAL ;
    SHAPE ABUTMENT ;
    PORT
      LAYER met2 ;
      RECT 94.690 1163.740 94.830 1164.160 ;
    END
  END rw0_rd_out[66]
  PIN rw0_rd_out[67]
    DIRECTION OUTPUT ;
    USE SIGNAL ;
    SHAPE ABUTMENT ;
    PORT
      LAYER met2 ;
      RECT 103.890 1163.740 104.030 1164.160 ;
    END
  END rw0_rd_out[67]
  PIN rw0_rd_out[68]
    DIRECTION OUTPUT ;
    USE SIGNAL ;
    SHAPE ABUTMENT ;
    PORT
      LAYER met2 ;
      RECT 113.090 1163.740 113.230 1164.160 ;
    END
  END rw0_rd_out[68]
  PIN rw0_rd_out[69]
    DIRECTION OUTPUT ;
    USE SIGNAL ;
    SHAPE ABUTMENT ;
    PORT
      LAYER met2 ;
      RECT 122.290 1163.740 122.430 1164.160 ;
    END
  END rw0_rd_out[69]
  PIN rw0_rd_out[70]
    DIRECTION OUTPUT ;
    USE SIGNAL ;
    SHAPE ABUTMENT ;
    PORT
      LAYER met2 ;
      RECT 131.490 1163.740 131.630 1164.160 ;
    END
  END rw0_rd_out[70]
  PIN rw0_rd_out[71]
    DIRECTION OUTPUT ;
    USE SIGNAL ;
    SHAPE ABUTMENT ;
    PORT
      LAYER met2 ;
      RECT 140.690 1163.740 140.830 1164.160 ;
    END
  END rw0_rd_out[71]
  PIN rw0_rd_out[72]
    DIRECTION OUTPUT ;
    USE SIGNAL ;
    SHAPE ABUTMENT ;
    PORT
      LAYER met2 ;
      RECT 149.890 1163.740 150.030 1164.160 ;
    END
  END rw0_rd_out[72]
  PIN rw0_rd_out[73]
    DIRECTION OUTPUT ;
    USE SIGNAL ;
    SHAPE ABUTMENT ;
    PORT
      LAYER met2 ;
      RECT 159.090 1163.740 159.230 1164.160 ;
    END
  END rw0_rd_out[73]
  PIN rw0_rd_out[74]
    DIRECTION OUTPUT ;
    USE SIGNAL ;
    SHAPE ABUTMENT ;
    PORT
      LAYER met2 ;
      RECT 168.290 1163.740 168.430 1164.160 ;
    END
  END rw0_rd_out[74]
  PIN rw0_rd_out[75]
    DIRECTION OUTPUT ;
    USE SIGNAL ;
    SHAPE ABUTMENT ;
    PORT
      LAYER met2 ;
      RECT 177.490 1163.740 177.630 1164.160 ;
    END
  END rw0_rd_out[75]
  PIN rw0_rd_out[76]
    DIRECTION OUTPUT ;
    USE SIGNAL ;
    SHAPE ABUTMENT ;
    PORT
      LAYER met2 ;
      RECT 186.690 1163.740 186.830 1164.160 ;
    END
  END rw0_rd_out[76]
  PIN rw0_rd_out[77]
    DIRECTION OUTPUT ;
    USE SIGNAL ;
    SHAPE ABUTMENT ;
    PORT
      LAYER met2 ;
      RECT 195.890 1163.740 196.030 1164.160 ;
    END
  END rw0_rd_out[77]
  PIN rw0_rd_out[78]
    DIRECTION OUTPUT ;
    USE SIGNAL ;
    SHAPE ABUTMENT ;
    PORT
      LAYER met2 ;
      RECT 205.090 1163.740 205.230 1164.160 ;
    END
  END rw0_rd_out[78]
  PIN rw0_rd_out[79]
    DIRECTION OUTPUT ;
    USE SIGNAL ;
    SHAPE ABUTMENT ;
    PORT
      LAYER met2 ;
      RECT 214.290 1163.740 214.430 1164.160 ;
    END
  END rw0_rd_out[79]
  PIN rw0_rd_out[80]
    DIRECTION OUTPUT ;
    USE SIGNAL ;
    SHAPE ABUTMENT ;
    PORT
      LAYER met2 ;
      RECT 223.490 1163.740 223.630 1164.160 ;
    END
  END rw0_rd_out[80]
  PIN rw0_rd_out[81]
    DIRECTION OUTPUT ;
    USE SIGNAL ;
    SHAPE ABUTMENT ;
    PORT
      LAYER met2 ;
      RECT 232.690 1163.740 232.830 1164.160 ;
    END
  END rw0_rd_out[81]
  PIN rw0_rd_out[82]
    DIRECTION OUTPUT ;
    USE SIGNAL ;
    SHAPE ABUTMENT ;
    PORT
      LAYER met2 ;
      RECT 241.890 1163.740 242.030 1164.160 ;
    END
  END rw0_rd_out[82]
  PIN rw0_rd_out[83]
    DIRECTION OUTPUT ;
    USE SIGNAL ;
    SHAPE ABUTMENT ;
    PORT
      LAYER met2 ;
      RECT 251.090 1163.740 251.230 1164.160 ;
    END
  END rw0_rd_out[83]
  PIN rw0_rd_out[84]
    DIRECTION OUTPUT ;
    USE SIGNAL ;
    SHAPE ABUTMENT ;
    PORT
      LAYER met2 ;
      RECT 260.290 1163.740 260.430 1164.160 ;
    END
  END rw0_rd_out[84]
  PIN rw0_rd_out[85]
    DIRECTION OUTPUT ;
    USE SIGNAL ;
    SHAPE ABUTMENT ;
    PORT
      LAYER met2 ;
      RECT 269.490 1163.740 269.630 1164.160 ;
    END
  END rw0_rd_out[85]
  PIN rw0_rd_out[86]
    DIRECTION OUTPUT ;
    USE SIGNAL ;
    SHAPE ABUTMENT ;
    PORT
      LAYER met2 ;
      RECT 278.690 1163.740 278.830 1164.160 ;
    END
  END rw0_rd_out[86]
  PIN rw0_rd_out[87]
    DIRECTION OUTPUT ;
    USE SIGNAL ;
    SHAPE ABUTMENT ;
    PORT
      LAYER met2 ;
      RECT 287.890 1163.740 288.030 1164.160 ;
    END
  END rw0_rd_out[87]
  PIN rw0_rd_out[88]
    DIRECTION OUTPUT ;
    USE SIGNAL ;
    SHAPE ABUTMENT ;
    PORT
      LAYER met2 ;
      RECT 297.090 1163.740 297.230 1164.160 ;
    END
  END rw0_rd_out[88]
  PIN rw0_rd_out[89]
    DIRECTION OUTPUT ;
    USE SIGNAL ;
    SHAPE ABUTMENT ;
    PORT
      LAYER met2 ;
      RECT 306.290 1163.740 306.430 1164.160 ;
    END
  END rw0_rd_out[89]
  PIN rw0_rd_out[90]
    DIRECTION OUTPUT ;
    USE SIGNAL ;
    SHAPE ABUTMENT ;
    PORT
      LAYER met2 ;
      RECT 315.490 1163.740 315.630 1164.160 ;
    END
  END rw0_rd_out[90]
  PIN rw0_rd_out[91]
    DIRECTION OUTPUT ;
    USE SIGNAL ;
    SHAPE ABUTMENT ;
    PORT
      LAYER met2 ;
      RECT 324.690 1163.740 324.830 1164.160 ;
    END
  END rw0_rd_out[91]
  PIN rw0_rd_out[92]
    DIRECTION OUTPUT ;
    USE SIGNAL ;
    SHAPE ABUTMENT ;
    PORT
      LAYER met2 ;
      RECT 333.890 1163.740 334.030 1164.160 ;
    END
  END rw0_rd_out[92]
  PIN rw0_rd_out[93]
    DIRECTION OUTPUT ;
    USE SIGNAL ;
    SHAPE ABUTMENT ;
    PORT
      LAYER met2 ;
      RECT 343.090 1163.740 343.230 1164.160 ;
    END
  END rw0_rd_out[93]
  PIN rw0_rd_out[94]
    DIRECTION OUTPUT ;
    USE SIGNAL ;
    SHAPE ABUTMENT ;
    PORT
      LAYER met2 ;
      RECT 352.290 1163.740 352.430 1164.160 ;
    END
  END rw0_rd_out[94]
  PIN rw0_rd_out[95]
    DIRECTION OUTPUT ;
    USE SIGNAL ;
    SHAPE ABUTMENT ;
    PORT
      LAYER met2 ;
      RECT 361.490 1163.740 361.630 1164.160 ;
    END
  END rw0_rd_out[95]
  PIN rw0_rd_out[96]
    DIRECTION OUTPUT ;
    USE SIGNAL ;
    SHAPE ABUTMENT ;
    PORT
      LAYER met2 ;
      RECT 370.690 1163.740 370.830 1164.160 ;
    END
  END rw0_rd_out[96]
  PIN rw0_rd_out[97]
    DIRECTION OUTPUT ;
    USE SIGNAL ;
    SHAPE ABUTMENT ;
    PORT
      LAYER met2 ;
      RECT 379.890 1163.740 380.030 1164.160 ;
    END
  END rw0_rd_out[97]
  PIN rw0_rd_out[98]
    DIRECTION OUTPUT ;
    USE SIGNAL ;
    SHAPE ABUTMENT ;
    PORT
      LAYER met2 ;
      RECT 389.090 1163.740 389.230 1164.160 ;
    END
  END rw0_rd_out[98]
  PIN rw0_rd_out[99]
    DIRECTION OUTPUT ;
    USE SIGNAL ;
    SHAPE ABUTMENT ;
    PORT
      LAYER met2 ;
      RECT 398.290 1163.740 398.430 1164.160 ;
    END
  END rw0_rd_out[99]
  PIN rw0_rd_out[100]
    DIRECTION OUTPUT ;
    USE SIGNAL ;
    SHAPE ABUTMENT ;
    PORT
      LAYER met2 ;
      RECT 407.490 1163.740 407.630 1164.160 ;
    END
  END rw0_rd_out[100]
  PIN rw0_rd_out[101]
    DIRECTION OUTPUT ;
    USE SIGNAL ;
    SHAPE ABUTMENT ;
    PORT
      LAYER met2 ;
      RECT 416.690 1163.740 416.830 1164.160 ;
    END
  END rw0_rd_out[101]
  PIN rw0_rd_out[102]
    DIRECTION OUTPUT ;
    USE SIGNAL ;
    SHAPE ABUTMENT ;
    PORT
      LAYER met2 ;
      RECT 425.890 1163.740 426.030 1164.160 ;
    END
  END rw0_rd_out[102]
  PIN rw0_rd_out[103]
    DIRECTION OUTPUT ;
    USE SIGNAL ;
    SHAPE ABUTMENT ;
    PORT
      LAYER met2 ;
      RECT 435.090 1163.740 435.230 1164.160 ;
    END
  END rw0_rd_out[103]
  PIN rw0_rd_out[104]
    DIRECTION OUTPUT ;
    USE SIGNAL ;
    SHAPE ABUTMENT ;
    PORT
      LAYER met2 ;
      RECT 444.290 1163.740 444.430 1164.160 ;
    END
  END rw0_rd_out[104]
  PIN rw0_rd_out[105]
    DIRECTION OUTPUT ;
    USE SIGNAL ;
    SHAPE ABUTMENT ;
    PORT
      LAYER met2 ;
      RECT 453.490 1163.740 453.630 1164.160 ;
    END
  END rw0_rd_out[105]
  PIN rw0_rd_out[106]
    DIRECTION OUTPUT ;
    USE SIGNAL ;
    SHAPE ABUTMENT ;
    PORT
      LAYER met2 ;
      RECT 462.690 1163.740 462.830 1164.160 ;
    END
  END rw0_rd_out[106]
  PIN rw0_rd_out[107]
    DIRECTION OUTPUT ;
    USE SIGNAL ;
    SHAPE ABUTMENT ;
    PORT
      LAYER met2 ;
      RECT 471.890 1163.740 472.030 1164.160 ;
    END
  END rw0_rd_out[107]
  PIN rw0_rd_out[108]
    DIRECTION OUTPUT ;
    USE SIGNAL ;
    SHAPE ABUTMENT ;
    PORT
      LAYER met2 ;
      RECT 481.090 1163.740 481.230 1164.160 ;
    END
  END rw0_rd_out[108]
  PIN rw0_rd_out[109]
    DIRECTION OUTPUT ;
    USE SIGNAL ;
    SHAPE ABUTMENT ;
    PORT
      LAYER met2 ;
      RECT 490.290 1163.740 490.430 1164.160 ;
    END
  END rw0_rd_out[109]
  PIN rw0_rd_out[110]
    DIRECTION OUTPUT ;
    USE SIGNAL ;
    SHAPE ABUTMENT ;
    PORT
      LAYER met2 ;
      RECT 499.490 1163.740 499.630 1164.160 ;
    END
  END rw0_rd_out[110]
  PIN rw0_rd_out[111]
    DIRECTION OUTPUT ;
    USE SIGNAL ;
    SHAPE ABUTMENT ;
    PORT
      LAYER met2 ;
      RECT 508.690 1163.740 508.830 1164.160 ;
    END
  END rw0_rd_out[111]
  PIN rw0_rd_out[112]
    DIRECTION OUTPUT ;
    USE SIGNAL ;
    SHAPE ABUTMENT ;
    PORT
      LAYER met2 ;
      RECT 517.890 1163.740 518.030 1164.160 ;
    END
  END rw0_rd_out[112]
  PIN rw0_rd_out[113]
    DIRECTION OUTPUT ;
    USE SIGNAL ;
    SHAPE ABUTMENT ;
    PORT
      LAYER met2 ;
      RECT 527.090 1163.740 527.230 1164.160 ;
    END
  END rw0_rd_out[113]
  PIN rw0_rd_out[114]
    DIRECTION OUTPUT ;
    USE SIGNAL ;
    SHAPE ABUTMENT ;
    PORT
      LAYER met2 ;
      RECT 536.290 1163.740 536.430 1164.160 ;
    END
  END rw0_rd_out[114]
  PIN rw0_rd_out[115]
    DIRECTION OUTPUT ;
    USE SIGNAL ;
    SHAPE ABUTMENT ;
    PORT
      LAYER met2 ;
      RECT 545.490 1163.740 545.630 1164.160 ;
    END
  END rw0_rd_out[115]
  PIN rw0_rd_out[116]
    DIRECTION OUTPUT ;
    USE SIGNAL ;
    SHAPE ABUTMENT ;
    PORT
      LAYER met2 ;
      RECT 554.690 1163.740 554.830 1164.160 ;
    END
  END rw0_rd_out[116]
  PIN rw0_rd_out[117]
    DIRECTION OUTPUT ;
    USE SIGNAL ;
    SHAPE ABUTMENT ;
    PORT
      LAYER met2 ;
      RECT 563.890 1163.740 564.030 1164.160 ;
    END
  END rw0_rd_out[117]
  PIN rw0_rd_out[118]
    DIRECTION OUTPUT ;
    USE SIGNAL ;
    SHAPE ABUTMENT ;
    PORT
      LAYER met2 ;
      RECT 573.090 1163.740 573.230 1164.160 ;
    END
  END rw0_rd_out[118]
  PIN rw0_rd_out[119]
    DIRECTION OUTPUT ;
    USE SIGNAL ;
    SHAPE ABUTMENT ;
    PORT
      LAYER met2 ;
      RECT 582.290 1163.740 582.430 1164.160 ;
    END
  END rw0_rd_out[119]
  PIN rw0_rd_out[120]
    DIRECTION OUTPUT ;
    USE SIGNAL ;
    SHAPE ABUTMENT ;
    PORT
      LAYER met2 ;
      RECT 591.490 1163.740 591.630 1164.160 ;
    END
  END rw0_rd_out[120]
  PIN rw0_rd_out[121]
    DIRECTION OUTPUT ;
    USE SIGNAL ;
    SHAPE ABUTMENT ;
    PORT
      LAYER met2 ;
      RECT 600.690 1163.740 600.830 1164.160 ;
    END
  END rw0_rd_out[121]
  PIN rw0_rd_out[122]
    DIRECTION OUTPUT ;
    USE SIGNAL ;
    SHAPE ABUTMENT ;
    PORT
      LAYER met2 ;
      RECT 609.890 1163.740 610.030 1164.160 ;
    END
  END rw0_rd_out[122]
  PIN rw0_rd_out[123]
    DIRECTION OUTPUT ;
    USE SIGNAL ;
    SHAPE ABUTMENT ;
    PORT
      LAYER met2 ;
      RECT 619.090 1163.740 619.230 1164.160 ;
    END
  END rw0_rd_out[123]
  PIN rw0_rd_out[124]
    DIRECTION OUTPUT ;
    USE SIGNAL ;
    SHAPE ABUTMENT ;
    PORT
      LAYER met2 ;
      RECT 628.290 1163.740 628.430 1164.160 ;
    END
  END rw0_rd_out[124]
  PIN rw0_rd_out[125]
    DIRECTION OUTPUT ;
    USE SIGNAL ;
    SHAPE ABUTMENT ;
    PORT
      LAYER met2 ;
      RECT 637.490 1163.740 637.630 1164.160 ;
    END
  END rw0_rd_out[125]
  PIN rw0_rd_out[126]
    DIRECTION OUTPUT ;
    USE SIGNAL ;
    SHAPE ABUTMENT ;
    PORT
      LAYER met2 ;
      RECT 646.690 1163.740 646.830 1164.160 ;
    END
  END rw0_rd_out[126]
  PIN rw0_rd_out[127]
    DIRECTION OUTPUT ;
    USE SIGNAL ;
    SHAPE ABUTMENT ;
    PORT
      LAYER met2 ;
      RECT 655.890 1163.740 656.030 1164.160 ;
    END
  END rw0_rd_out[127]
  PIN rw0_addr_in[0]
    DIRECTION INPUT ;
    USE SIGNAL ;
    SHAPE ABUTMENT ;
    PORT
      LAYER met3 ;
      RECT 0.000 1007.610 0.900 1007.910 ;
    END
  END rw0_addr_in[0]
  PIN rw0_addr_in[1]
    DIRECTION INPUT ;
    USE SIGNAL ;
    SHAPE ABUTMENT ;
    PORT
      LAYER met3 ;
      RECT 0.000 1035.490 0.900 1035.790 ;
    END
  END rw0_addr_in[1]
  PIN rw0_addr_in[2]
    DIRECTION INPUT ;
    USE SIGNAL ;
    SHAPE ABUTMENT ;
    PORT
      LAYER met3 ;
      RECT 0.000 1063.370 0.900 1063.670 ;
    END
  END rw0_addr_in[2]
  PIN rw0_addr_in[3]
    DIRECTION INPUT ;
    USE SIGNAL ;
    SHAPE ABUTMENT ;
    PORT
      LAYER met3 ;
      RECT 0.000 1091.250 0.900 1091.550 ;
    END
  END rw0_addr_in[3]
  PIN rw0_addr_in[4]
    DIRECTION INPUT ;
    USE SIGNAL ;
    SHAPE ABUTMENT ;
    PORT
      LAYER met3 ;
      RECT 0.000 1119.130 0.900 1119.430 ;
    END
  END rw0_addr_in[4]
  PIN rw0_addr_in[5]
    DIRECTION INPUT ;
    USE SIGNAL ;
    SHAPE ABUTMENT ;
    PORT
      LAYER met3 ;
      RECT 714.860 1007.610 715.760 1007.910 ;
    END
  END rw0_addr_in[5]
  PIN rw0_addr_in[6]
    DIRECTION INPUT ;
    USE SIGNAL ;
    SHAPE ABUTMENT ;
    PORT
      LAYER met3 ;
      RECT 714.860 1035.490 715.760 1035.790 ;
    END
  END rw0_addr_in[6]
  PIN rw0_addr_in[7]
    DIRECTION INPUT ;
    USE SIGNAL ;
    SHAPE ABUTMENT ;
    PORT
      LAYER met3 ;
      RECT 714.860 1063.370 715.760 1063.670 ;
    END
  END rw0_addr_in[7]
  PIN rw0_addr_in[8]
    DIRECTION INPUT ;
    USE SIGNAL ;
    SHAPE ABUTMENT ;
    PORT
      LAYER met3 ;
      RECT 714.860 1091.250 715.760 1091.550 ;
    END
  END rw0_addr_in[8]
  PIN rw0_we_in
    DIRECTION INPUT ;
    USE SIGNAL ;
    SHAPE ABUTMENT ;
    PORT
      LAYER met2 ;
      RECT 665.090 1163.740 665.230 1164.160 ;
    END
  END rw0_we_in
  PIN rw0_ce_in
    DIRECTION INPUT ;
    USE SIGNAL ;
    SHAPE ABUTMENT ;
    PORT
      LAYER met2 ;
      RECT 674.290 1163.740 674.430 1164.160 ;
    END
  END rw0_ce_in
  PIN rw0_clk
    DIRECTION INPUT ;
    USE SIGNAL ;
    SHAPE ABUTMENT ;
    PORT
      LAYER met2 ;
      RECT 683.490 1163.740 683.630 1164.160 ;
    END
  END rw0_clk
  PIN VSS
    DIRECTION INOUT ;
    USE GROUND ;
    PORT
      LAYER met4 ;
      RECT 2.160 4.080 3.360 1160.080 ;
      RECT 13.040 4.080 14.240 1160.080 ;
      RECT 23.920 4.080 25.120 1160.080 ;
      RECT 34.800 4.080 36.000 1160.080 ;
      RECT 45.680 4.080 46.880 1160.080 ;
      RECT 56.560 4.080 57.760 1160.080 ;
      RECT 67.440 4.080 68.640 1160.080 ;
      RECT 78.320 4.080 79.520 1160.080 ;
      RECT 89.200 4.080 90.400 1160.080 ;
      RECT 100.080 4.080 101.280 1160.080 ;
      RECT 110.960 4.080 112.160 1160.080 ;
      RECT 121.840 4.080 123.040 1160.080 ;
      RECT 132.720 4.080 133.920 1160.080 ;
      RECT 143.600 4.080 144.800 1160.080 ;
      RECT 154.480 4.080 155.680 1160.080 ;
      RECT 165.360 4.080 166.560 1160.080 ;
      RECT 176.240 4.080 177.440 1160.080 ;
      RECT 187.120 4.080 188.320 1160.080 ;
      RECT 198.000 4.080 199.200 1160.080 ;
      RECT 208.880 4.080 210.080 1160.080 ;
      RECT 219.760 4.080 220.960 1160.080 ;
      RECT 230.640 4.080 231.840 1160.080 ;
      RECT 241.520 4.080 242.720 1160.080 ;
      RECT 252.400 4.080 253.600 1160.080 ;
      RECT 263.280 4.080 264.480 1160.080 ;
      RECT 274.160 4.080 275.360 1160.080 ;
      RECT 285.040 4.080 286.240 1160.080 ;
      RECT 295.920 4.080 297.120 1160.080 ;
      RECT 306.800 4.080 308.000 1160.080 ;
      RECT 317.680 4.080 318.880 1160.080 ;
      RECT 328.560 4.080 329.760 1160.080 ;
      RECT 339.440 4.080 340.640 1160.080 ;
      RECT 350.320 4.080 351.520 1160.080 ;
      RECT 361.200 4.080 362.400 1160.080 ;
      RECT 372.080 4.080 373.280 1160.080 ;
      RECT 382.960 4.080 384.160 1160.080 ;
      RECT 393.840 4.080 395.040 1160.080 ;
      RECT 404.720 4.080 405.920 1160.080 ;
      RECT 415.600 4.080 416.800 1160.080 ;
      RECT 426.480 4.080 427.680 1160.080 ;
      RECT 437.360 4.080 438.560 1160.080 ;
      RECT 448.240 4.080 449.440 1160.080 ;
      RECT 459.120 4.080 460.320 1160.080 ;
      RECT 470.000 4.080 471.200 1160.080 ;
      RECT 480.880 4.080 482.080 1160.080 ;
      RECT 491.760 4.080 492.960 1160.080 ;
      RECT 502.640 4.080 503.840 1160.080 ;
      RECT 513.520 4.080 514.720 1160.080 ;
      RECT 524.400 4.080 525.600 1160.080 ;
      RECT 535.280 4.080 536.480 1160.080 ;
      RECT 546.160 4.080 547.360 1160.080 ;
      RECT 557.040 4.080 558.240 1160.080 ;
      RECT 567.920 4.080 569.120 1160.080 ;
      RECT 578.800 4.080 580.000 1160.080 ;
      RECT 589.680 4.080 590.880 1160.080 ;
      RECT 600.560 4.080 601.760 1160.080 ;
      RECT 611.440 4.080 612.640 1160.080 ;
      RECT 622.320 4.080 623.520 1160.080 ;
      RECT 633.200 4.080 634.400 1160.080 ;
      RECT 644.080 4.080 645.280 1160.080 ;
      RECT 654.960 4.080 656.160 1160.080 ;
      RECT 665.840 4.080 667.040 1160.080 ;
      RECT 676.720 4.080 677.920 1160.080 ;
      RECT 687.600 4.080 688.800 1160.080 ;
      RECT 698.480 4.080 699.680 1160.080 ;
      RECT 709.360 4.080 710.560 1160.080 ;
    END
  END VSS
  PIN VDD
    DIRECTION INOUT ;
    USE POWER ;
    PORT
      LAYER met4 ;
      RECT 7.600 4.080 8.800 1160.080 ;
      RECT 18.480 4.080 19.680 1160.080 ;
      RECT 29.360 4.080 30.560 1160.080 ;
      RECT 40.240 4.080 41.440 1160.080 ;
      RECT 51.120 4.080 52.320 1160.080 ;
      RECT 62.000 4.080 63.200 1160.080 ;
      RECT 72.880 4.080 74.080 1160.080 ;
      RECT 83.760 4.080 84.960 1160.080 ;
      RECT 94.640 4.080 95.840 1160.080 ;
      RECT 105.520 4.080 106.720 1160.080 ;
      RECT 116.400 4.080 117.600 1160.080 ;
      RECT 127.280 4.080 128.480 1160.080 ;
      RECT 138.160 4.080 139.360 1160.080 ;
      RECT 149.040 4.080 150.240 1160.080 ;
      RECT 159.920 4.080 161.120 1160.080 ;
      RECT 170.800 4.080 172.000 1160.080 ;
      RECT 181.680 4.080 182.880 1160.080 ;
      RECT 192.560 4.080 193.760 1160.080 ;
      RECT 203.440 4.080 204.640 1160.080 ;
      RECT 214.320 4.080 215.520 1160.080 ;
      RECT 225.200 4.080 226.400 1160.080 ;
      RECT 236.080 4.080 237.280 1160.080 ;
      RECT 246.960 4.080 248.160 1160.080 ;
      RECT 257.840 4.080 259.040 1160.080 ;
      RECT 268.720 4.080 269.920 1160.080 ;
      RECT 279.600 4.080 280.800 1160.080 ;
      RECT 290.480 4.080 291.680 1160.080 ;
      RECT 301.360 4.080 302.560 1160.080 ;
      RECT 312.240 4.080 313.440 1160.080 ;
      RECT 323.120 4.080 324.320 1160.080 ;
      RECT 334.000 4.080 335.200 1160.080 ;
      RECT 344.880 4.080 346.080 1160.080 ;
      RECT 355.760 4.080 356.960 1160.080 ;
      RECT 366.640 4.080 367.840 1160.080 ;
      RECT 377.520 4.080 378.720 1160.080 ;
      RECT 388.400 4.080 389.600 1160.080 ;
      RECT 399.280 4.080 400.480 1160.080 ;
      RECT 410.160 4.080 411.360 1160.080 ;
      RECT 421.040 4.080 422.240 1160.080 ;
      RECT 431.920 4.080 433.120 1160.080 ;
      RECT 442.800 4.080 444.000 1160.080 ;
      RECT 453.680 4.080 454.880 1160.080 ;
      RECT 464.560 4.080 465.760 1160.080 ;
      RECT 475.440 4.080 476.640 1160.080 ;
      RECT 486.320 4.080 487.520 1160.080 ;
      RECT 497.200 4.080 498.400 1160.080 ;
      RECT 508.080 4.080 509.280 1160.080 ;
      RECT 518.960 4.080 520.160 1160.080 ;
      RECT 529.840 4.080 531.040 1160.080 ;
      RECT 540.720 4.080 541.920 1160.080 ;
      RECT 551.600 4.080 552.800 1160.080 ;
      RECT 562.480 4.080 563.680 1160.080 ;
      RECT 573.360 4.080 574.560 1160.080 ;
      RECT 584.240 4.080 585.440 1160.080 ;
      RECT 595.120 4.080 596.320 1160.080 ;
      RECT 606.000 4.080 607.200 1160.080 ;
      RECT 616.880 4.080 618.080 1160.080 ;
      RECT 627.760 4.080 628.960 1160.080 ;
      RECT 638.640 4.080 639.840 1160.080 ;
      RECT 649.520 4.080 650.720 1160.080 ;
      RECT 660.400 4.080 661.600 1160.080 ;
      RECT 671.280 4.080 672.480 1160.080 ;
      RECT 682.160 4.080 683.360 1160.080 ;
      RECT 693.040 4.080 694.240 1160.080 ;
      RECT 703.920 4.080 705.120 1160.080 ;
    END
  END VDD
  OBS
    LAYER met1 ;
    RECT 0 0 715.760 1164.160 ;
    LAYER met2 ;
    RECT 0 0 715.760 1164.160 ;
    LAYER met3 ;
    RECT 0 0 715.760 1164.160 ;
    LAYER met4 ;
    RECT 0 0 715.760 1164.160 ;
  END
END fakeram_512x128_1rw

END LIBRARY
